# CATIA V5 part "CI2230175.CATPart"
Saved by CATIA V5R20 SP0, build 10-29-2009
Part number: CI2230175
Bounding box of the stored display mesh (mm): x -29 to 29, y -23.836 to 220, z -41.554 to 32.071
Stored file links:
  C:\Users\Raffaele\Desktop\3D X SITO CF\BOLEX\19-INCLINED ASSEMBLY REF_CI\CI2230175.CATPart

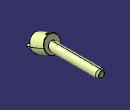
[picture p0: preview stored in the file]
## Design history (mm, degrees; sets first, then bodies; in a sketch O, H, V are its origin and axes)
Set1
  DatumSurface1 to DatumSurface16 "MANIFOLD_SOLID_BREP #395"
  DatumSurface17 to DatumSurface39 "MANIFOLD_SOLID_BREP #1169"
Body1 (main body)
